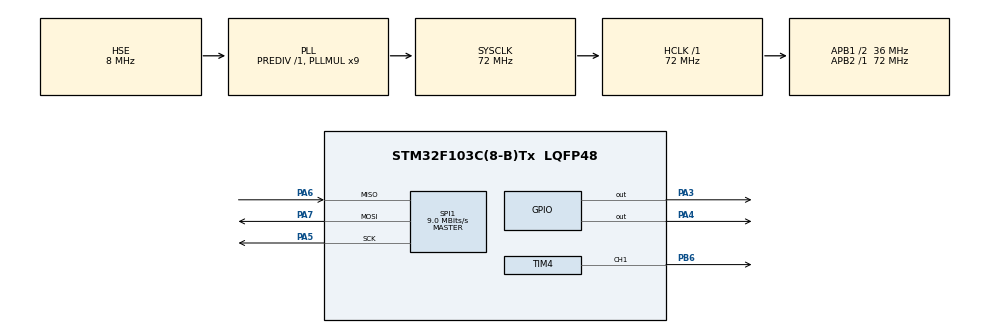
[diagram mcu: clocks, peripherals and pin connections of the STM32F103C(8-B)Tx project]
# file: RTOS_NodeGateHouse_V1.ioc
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FREERTOS.HEAP_NUMBER=4
FREERTOS.MEMORY_ALLOCATION=0
FREERTOS.Queues01=xQueueSendDataLCD,5,uint16_t,0,Dynamic,NULL,NULL
FREERTOS.Tasks01=KeyPad,0,128,TaskKeypad,Default,NULL,Dynamic,NULL,NULL;Card,-3,128,TaskCard,Default,NULL,Dynamic,NULL,NULL;LCD,-3,128,TaskLCD,Default,NULL,Dynamic,NULL,NULL;Pass,-3,128,TaskPass,Default,NULL,Dynamic,NULL,NULL;NRF,-3,128,TaskNRF,Default,NULL,Dynamic,NULL,NULL
FREERTOS.configTOTAL_HEAP_SIZE=3864
Mcu.Family=STM32F1
Mcu.Name=STM32F103C(8-B)Tx
Mcu.Package=LQFP48
NVIC.PriorityGroup=NVIC_PRIORITYGROUP_4
PA3.Signal=GPIO_Output
PA4.Signal=GPIO_Output
PA5.Mode=Full_Duplex_Master
PA5.Signal=SPI1_SCK
PA6.Mode=Full_Duplex_Master
PA6.Signal=SPI1_MISO
PA7.Mode=Full_Duplex_Master
PA7.Signal=SPI1_MOSI
PB6.Signal=S_TIM4_CH1
PD0-OSC_IN.Mode=HSE-External-Oscillator
PD0-OSC_IN.Signal=RCC_OSC_IN
PD1-OSC_OUT.Mode=HSE-External-Oscillator
PD1-OSC_OUT.Signal=RCC_OSC_OUT
ProjectManager.HeapSize=0x200
ProjectManager.StackSize=0x400
ProjectManager.TargetToolchain=MDK-ARM V5
RCC.AHBFreq_Value=72000000
RCC.APB1CLKDivider=RCC_HCLK_DIV2
RCC.APB1Freq_Value=36000000
RCC.APB1TimFreq_Value=72000000
RCC.APB2Freq_Value=72000000
RCC.APB2TimFreq_Value=72000000
RCC.HCLKFreq_Value=72000000
RCC.PLLMUL=RCC_PLL_MUL9
RCC.PLLSourceVirtual=RCC_PLLSOURCE_HSE
RCC.SYSCLKFreq_VALUE=72000000
RCC.SYSCLKSource=RCC_SYSCLKSOURCE_PLLCLK
RCC.USBFreq_Value=72000000
SH.S_TIM4_CH1.0=TIM4_CH1,PWM Generation1 CH1
SPI1.BaudRatePrescaler=SPI_BAUDRATEPRESCALER_8
SPI1.CalculateBaudRate=9.0 MBits/s
SPI1.Direction=SPI_DIRECTION_2LINES
SPI1.Mode=SPI_MODE_MASTER
SPI1.VirtualType=VM_MASTER
TIM4.Channel-PWM\ Generation1\ CH1=TIM_CHANNEL_1
VP_FREERTOS_VS_CMSIS_V1.Mode=CMSIS_V1
VP_SYS_VS_ND.Mode=No_Debug
VP_TIM2_VS_ClockSourceINT.Mode=Internal
VP_TIM4_VS_ClockSourceINT.Mode=Internal
board=custom

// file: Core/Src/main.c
#include "main.h"
#include "cmsis_os.h"
#include "TASK_DATA.h"
#include "RFID_RCC522.h"
#include "MY_NRF24.h"
#include "LCD20X4.h"

SPI_HandleTypeDef hspi1;

TIM_HandleTypeDef htim2;
TIM_HandleTypeDef htim4;

osThreadId KeyPadHandle;
osThreadId CardHandle;
osThreadId LCDHandle;
osThreadId AddHandle;
osThreadId NRFHandle;

osMessageQId xQueueDataTaskCradSendCardID_State_tHandle;
osMessageQId xQueueDataTaskCardSendMasterCard_State_tHandle;
osMessageQId xQueueDataTaskCardSendData_Card_tHandle;

void SystemClock_Config(void);
static void MX_GPIO_Init(void);
static void MX_TIM2_Init(void);
static void MX_TIM4_Init(void);
static void MX_SPI1_Init(void);
void TaskKeypad(void const * argument);
void TaskCard(void const * argument);
void TaskLCD(void const * argument);
void TaskAdd(void const* argument);
void TaskNRF(void const * argument);

int main(void)
{

  HAL_Init();
  SystemClock_Config();

  MX_GPIO_Init();
  MX_TIM2_Init();
  MX_TIM4_Init();
  MX_SPI1_Init();
	MFRC522_Init();
	LCD20X4_Init();

  //config NRF
	NRF24_Begin(hspi1,SPI1_Port,SPI1_CS_PIN,SPI1_CE_PIN);
    NRF24_OpenWritingPipe(Address_NodeGate);
    NRF24_OpenReadingPipe(1,Address_NodeGate);
    NRF24_SetPALevel(RF24_PA_0dB);
    NRF24_SetDataRate(RF24_250KBPS);
    NRF24_SetChannel(52);
    NRF24_EnableDynamicPayloads();
    NRF24_SetAutoAck(true);
    NRF24_SetRetries(10,15);
    NRF24_StartListening();

//Create Queue

  osMessageQDef(SendCardID_State_t, 5, sizeof(CardID_State_t));
  xQueueDataTaskCradSendCardID_State_tHandle = osMessageCreate(osMessageQ(SendCardID_State_t), NULL);

  osMessageQDef(SendMasterCard_State_t, 5, sizeof(MasterCard_State_t));
  xQueueDataTaskCardSendMasterCard_State_tHandle = osMessageCreate(osMessageQ(SendMasterCard_State_t), NULL);

  osMessageQDef(SendData_card_t, 16, sizeof(Data_Card_t));
  xQueueDataTaskCardSendData_Card_tHandle = osMessageCreate(osMessageQ(SendData_card_t), NULL);

 //Create Task

  osThreadDef(KeyPad, TaskKeypad, 1, 0, 128);
  KeyPadHandle = osThreadCreate(osThread(KeyPad), NULL);

  /* definition and creation of Card */
  osThreadDef(Card, TaskCard, 1, 0, 128);
  CardHandle = osThreadCreate(osThread(Card), NULL);

  /* definition and creation of LCD */
  osThreadDef(LCD, TaskLCD, 1, 0, 128);
  LCDHandle = osThreadCreate(osThread(LCD), NULL);

  /* definition and creation of Pass */
  osThreadDef(Add, TaskAdd, 2, 0, 128);
  AddHandle = osThreadCreate(osThread(Add), NULL);

  /* definition and creation of NRF */
  osThreadDef(NRF, TaskNRF, 1, 0, 128);
  NRFHandle = osThreadCreate(osThread(NRF), NULL);

  osKernelStart();

  while (1);
}

void SystemClock_Config(void)
{
  RCC_OscInitTypeDef RCC_OscInitStruct = {0};
  RCC_ClkInitTypeDef RCC_ClkInitStruct = {0};

  /** Initializes the RCC Oscillators according to the specified parameters
  * in the RCC_OscInitTypeDef structure.
  */
  RCC_OscInitStruct.OscillatorType = RCC_OSCILLATORTYPE_HSE;
  RCC_OscInitStruct.HSEState = RCC_HSE_ON;
  RCC_OscInitStruct.HSEPredivValue = RCC_HSE_PREDIV_DIV1;
  RCC_OscInitStruct.HSIState = RCC_HSI_ON;
  RCC_OscInitStruct.PLL.PLLState = RCC_PLL_ON;
  RCC_OscInitStruct.PLL.PLLSource = RCC_PLLSOURCE_HSE;
  RCC_OscInitStruct.PLL.PLLMUL = RCC_PLL_MUL9;
  if (HAL_RCC_OscConfig(&RCC_OscInitStruct) != HAL_OK)
  {
    Error_Handler();
  }

  /** Initializes the CPU, AHB and APB buses clocks
  */
  RCC_ClkInitStruct.ClockType = RCC_CLOCKTYPE_HCLK|RCC_CLOCKTYPE_SYSCLK
                              |RCC_CLOCKTYPE_PCLK1|RCC_CLOCKTYPE_PCLK2;
  RCC_ClkInitStruct.SYSCLKSource = RCC_SYSCLKSOURCE_PLLCLK;
  RCC_ClkInitStruct.AHBCLKDivider = RCC_SYSCLK_DIV1;
  RCC_ClkInitStruct.APB1CLKDivider = RCC_HCLK_DIV2;
  RCC_ClkInitStruct.APB2CLKDivider = RCC_HCLK_DIV1;

  if (HAL_RCC_ClockConfig(&RCC_ClkInitStruct, FLASH_LATENCY_2) != HAL_OK)
  {
    Error_Handler();
  }
}

static void MX_SPI1_Init(void)
{

  /* SPI1 parameter configuration*/
  hspi1.Instance = SPI1;
  hspi1.Init.Mode = SPI_MODE_MASTER;
  hspi1.Init.Direction = SPI_DIRECTION_2LINES;
  hspi1.Init.DataSize = SPI_DATASIZE_8BIT;
  hspi1.Init.CLKPolarity = SPI_POLARITY_LOW;
  hspi1.Init.CLKPhase = SPI_PHASE_1EDGE;
  hspi1.Init.NSS = SPI_NSS_SOFT;
  hspi1.Init.BaudRatePrescaler = SPI_BAUDRATEPRESCALER_8;
  hspi1.Init.FirstBit = SPI_FIRSTBIT_MSB;
  hspi1.Init.TIMode = SPI_TIMODE_DISABLE;
  hspi1.Init.CRCCalculation = SPI_CRCCALCULATION_DISABLE;
  hspi1.Init.CRCPolynomial = 10;
  if (HAL_SPI_Init(&hspi1) != HAL_OK)
  {
    Error_Handler();
  }

}

static void MX_TIM2_Init(void)
{

  TIM_ClockConfigTypeDef sClockSourceConfig = {0};
  TIM_MasterConfigTypeDef sMasterConfig = {0};

  htim2.Instance = TIM2;
  htim2.Init.Prescaler = 0;
  htim2.Init.CounterMode = TIM_COUNTERMODE_UP;
  htim2.Init.Period = 65535;
  htim2.Init.ClockDivision = TIM_CLOCKDIVISION_DIV1;
  htim2.Init.AutoReloadPreload = TIM_AUTORELOAD_PRELOAD_DISABLE;
  if (HAL_TIM_Base_Init(&htim2) != HAL_OK)
  {
    Error_Handler();
  }
  sClockSourceConfig.ClockSource = TIM_CLOCKSOURCE_INTERNAL;
  if (HAL_TIM_ConfigClockSource(&htim2, &sClockSourceConfig) != HAL_OK)
  {
    Error_Handler();
  }
  sMasterConfig.MasterOutputTrigger = TIM_TRGO_RESET;
  sMasterConfig.MasterSlaveMode = TIM_MASTERSLAVEMODE_DISABLE;
  if (HAL_TIMEx_MasterConfigSynchronization(&htim2, &sMasterConfig) != HAL_OK)
  {
    Error_Handler();
  }

}

static void MX_TIM4_Init(void)
{

  TIM_ClockConfigTypeDef sClockSourceConfig = {0};
  TIM_MasterConfigTypeDef sMasterConfig = {0};
  TIM_OC_InitTypeDef sConfigOC = {0};

  htim4.Instance = TIM4;
  htim4.Init.Prescaler = 0;
  htim4.Init.CounterMode = TIM_COUNTERMODE_UP;
  htim4.Init.Period = 65535;
  htim4.Init.ClockDivision = TIM_CLOCKDIVISION_DIV1;
  htim4.Init.AutoReloadPreload = TIM_AUTORELOAD_PRELOAD_DISABLE;
  if (HAL_TIM_Base_Init(&htim4) != HAL_OK)
  {
    Error_Handler();
  }
  sClockSourceConfig.ClockSource = TIM_CLOCKSOURCE_INTERNAL;
  if (HAL_TIM_ConfigClockSource(&htim4, &sClockSourceConfig) != HAL_OK)
  {
    Error_Handler();
  }
  if (HAL_TIM_PWM_Init(&htim4) != HAL_OK)
  {
    Error_Handler();
  }
  sMasterConfig.MasterOutputTrigger = TIM_TRGO_RESET;
  sMasterConfig.MasterSlaveMode = TIM_MASTERSLAVEMODE_DISABLE;
  if (HAL_TIMEx_MasterConfigSynchronization(&htim4, &sMasterConfig) != HAL_OK)
  {
    Error_Handler();
  }
  sConfigOC.OCMode = TIM_OCMODE_PWM1;
  sConfigOC.Pulse = 0;
  sConfigOC.OCPolarity = TIM_OCPOLARITY_HIGH;
  sConfigOC.OCFastMode = TIM_OCFAST_DISABLE;
  if (HAL_TIM_PWM_ConfigChannel(&htim4, &sConfigOC, TIM_CHANNEL_1) != HAL_OK)
  {
    Error_Handler();
  }
  HAL_TIM_MspPostInit(&htim4);

}

static void MX_GPIO_Init(void)
{
  GPIO_InitTypeDef GPIO_InitStruct = {0};

  /* GPIO Ports Clock Enable */
  __HAL_RCC_GPIOD_CLK_ENABLE();
  __HAL_RCC_GPIOA_CLK_ENABLE();
  __HAL_RCC_GPIOB_CLK_ENABLE();
  __HAL_RCC_GPIOC_CLK_ENABLE();
  /*Configure GPIO pin Output Level */
  HAL_GPIO_WritePin(GPIOA, CS_RFID_Pin|GPIO_PIN_8|GPIO_PIN_9, GPIO_PIN_RESET);

  /*Configure GPIO pin Output Level */
  HAL_GPIO_WritePin(GPIOB, GPIO_PIN_0|GPIO_PIN_1|GPIO_PIN_12|GPIO_PIN_13
                          |GPIO_PIN_14|GPIO_PIN_15, GPIO_PIN_RESET);

  GPIO_InitStruct.Pin = CS_RFID_Pin;
  GPIO_InitStruct.Mode = GPIO_MODE_OUTPUT_PP;
  GPIO_InitStruct.Pull = GPIO_PULLUP;
  GPIO_InitStruct.Speed = GPIO_SPEED_FREQ_LOW;
  HAL_GPIO_Init(GPIOA, &GPIO_InitStruct);

    /*Configure GPIO pins : PA8 PA9 */

   GPIO_InitStruct.Pin =GPIO_PIN_8|GPIO_PIN_9;
  GPIO_InitStruct.Mode = GPIO_MODE_OUTPUT_PP;
  GPIO_InitStruct.Pull = GPIO_PULLUP;
  GPIO_InitStruct.Speed = GPIO_SPEED_FREQ_LOW;
  HAL_GPIO_Init(GPIOA, &GPIO_InitStruct);

  /*Configure GPIO pins : PB0 PB1 */
  GPIO_InitStruct.Pin = GPIO_PIN_0|GPIO_PIN_1;
  GPIO_InitStruct.Mode = GPIO_MODE_OUTPUT_PP;
  GPIO_InitStruct.Pull = GPIO_PULLUP;
  GPIO_InitStruct.Speed = GPIO_SPEED_FREQ_LOW;
  HAL_GPIO_Init(GPIOB, &GPIO_InitStruct);

  GPIO_InitStruct.Pin = GPIO_PIN_7|GPIO_PIN_8;
  GPIO_InitStruct.Mode = GPIO_MODE_OUTPUT_PP;
  GPIO_InitStruct.Pull = GPIO_PULLUP;
  GPIO_InitStruct.Speed = GPIO_SPEED_FREQ_HIGH;
  HAL_GPIO_Init(GPIOB, &GPIO_InitStruct);
 /*Configure GPIO pins : PB12 PB13
                           PB14 PB15 */
 GPIO_InitStruct.Pin = GPIO_PIN_11|GPIO_PIN_12|GPIO_PIN_13
                          |GPIO_PIN_14|GPIO_PIN_15;
  GPIO_InitStruct.Mode = GPIO_MODE_OUTPUT_PP;
  GPIO_InitStruct.Pull = GPIO_PULLUP;
  GPIO_InitStruct.Speed = GPIO_SPEED_FREQ_LOW;
  HAL_GPIO_Init(GPIOB, &GPIO_InitStruct);

  /* configure GPIO pin:13 */

  GPIO_InitStruct.Pin = GPIO_PIN_13;
  GPIO_InitStruct.Mode = GPIO_MODE_OUTPUT_PP;
  GPIO_InitStruct.Pull = GPIO_NOPULL;
  GPIO_InitStruct.Speed = GPIO_SPEED_FREQ_LOW;
  HAL_GPIO_Init(GPIOC, &GPIO_InitStruct);

 /* Config GPIO KeyPad 4x4 */
	GPIO_InitStruct.Pin =ROW_3_Pin | ROW_4_Pin;
	GPIO_InitStruct.Mode = GPIO_MODE_INPUT;
	GPIO_InitStruct.Pull = GPIO_PULLUP;
	HAL_GPIO_Init(ROW_PORT_B, &GPIO_InitStruct);

	GPIO_InitStruct.Pin = ROW_1_Pin | ROW_2_Pin;
	GPIO_InitStruct.Mode = GPIO_MODE_INPUT;
	GPIO_InitStruct.Pull = GPIO_PULLUP;
	HAL_GPIO_Init(ROW_PORT, &GPIO_InitStruct);

	GPIO_InitStruct.Pin = COL_1_Pin | COL_2_Pin | COL_3_Pin | COL_4_Pin;
	GPIO_InitStruct.Mode = GPIO_MODE_OUTPUT_PP;
	GPIO_InitStruct.Speed = GPIO_SPEED_FREQ_LOW;
	HAL_GPIO_Init(COL_PORT, &GPIO_InitStruct);

}

void Error_Handler(void)
{
  __disable_irq();
  while (1)
  {
  }
}
